VERSION 5.7 ;
  NOWIREEXTENSIONATPIN ON ;
  DIVIDERCHAR "/" ;
  BUSBITCHARS "[]" ;
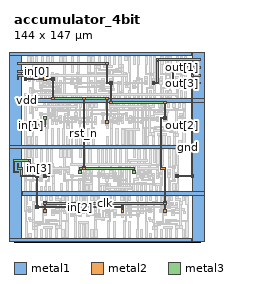
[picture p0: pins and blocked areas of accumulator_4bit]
MACRO accumulator_4bit
  CLASS BLOCK ;
  FOREIGN accumulator_4bit ;
  ORIGIN 6.000 0.000 ;
  SIZE 144.000 BY 147.000 ;
  PIN gnd
    USE GROUND ;
    PORT
      LAYER metal1 ;
        RECT 132.300 110.700 141.300 146.700 ;
        RECT 0.600 108.300 141.300 110.700 ;
        RECT 132.300 38.700 141.300 108.300 ;
        RECT 0.600 36.300 141.300 38.700 ;
        RECT 132.300 0.300 141.300 36.300 ;
    END
  END gnd
  PIN vdd
    USE POWER ;
    PORT
      LAYER metal1 ;
        RECT -9.300 144.300 131.400 146.700 ;
        RECT -9.300 74.700 -0.300 144.300 ;
        RECT -9.300 72.300 131.400 74.700 ;
        RECT -9.300 2.700 -0.300 72.300 ;
        RECT -9.300 0.300 131.400 2.700 ;
    END
  END vdd
  PIN clk
    PORT
      LAYER metal2 ;
        RECT 64.950 136.950 67.050 139.050 ;
        RECT 65.400 123.450 66.450 136.950 ;
        RECT 67.950 123.450 70.050 124.050 ;
        RECT 65.400 122.400 70.050 123.450 ;
        RECT 67.950 121.950 70.050 122.400 ;
        RECT 68.400 109.050 69.450 121.950 ;
        RECT 67.950 106.950 70.050 109.050 ;
        RECT 109.950 106.950 112.050 109.050 ;
        RECT 110.400 97.050 111.450 106.950 ;
        RECT 109.950 96.450 112.050 97.050 ;
        RECT 107.400 95.400 112.050 96.450 ;
        RECT 107.400 57.450 108.450 95.400 ;
        RECT 109.950 94.950 112.050 95.400 ;
        RECT 107.400 56.400 111.450 57.450 ;
        RECT 110.400 31.050 111.450 56.400 ;
        RECT 16.950 28.950 19.050 31.050 ;
        RECT 109.950 28.950 112.050 31.050 ;
        RECT 17.400 25.050 18.450 28.950 ;
        RECT 110.400 25.050 111.450 28.950 ;
        RECT 16.950 22.950 19.050 25.050 ;
        RECT 109.950 22.950 112.050 25.050 ;
      LAYER metal3 ;
        RECT 64.950 138.600 67.050 139.050 ;
        RECT -3.600 137.400 67.050 138.600 ;
        RECT 64.950 136.950 67.050 137.400 ;
        RECT 67.950 108.600 70.050 109.050 ;
        RECT 109.950 108.600 112.050 109.050 ;
        RECT 67.950 107.400 112.050 108.600 ;
        RECT 67.950 106.950 70.050 107.400 ;
        RECT 109.950 106.950 112.050 107.400 ;
        RECT 16.950 30.600 19.050 31.050 ;
        RECT 109.950 30.600 112.050 31.050 ;
        RECT 16.950 29.400 112.050 30.600 ;
        RECT 16.950 28.950 19.050 29.400 ;
        RECT 109.950 28.950 112.050 29.400 ;
    END
  END clk
  PIN rst_n
    PORT
      LAYER metal2 ;
        RECT 1.950 130.950 4.050 133.050 ;
        RECT 2.400 127.050 3.450 130.950 ;
        RECT 1.950 124.950 4.050 127.050 ;
        RECT 22.950 124.950 25.050 127.050 ;
        RECT 23.400 112.050 24.450 124.950 ;
        RECT 22.950 109.950 25.050 112.050 ;
        RECT 46.950 109.950 49.050 112.050 ;
        RECT 64.950 109.950 67.050 112.050 ;
        RECT 47.400 58.050 48.450 109.950 ;
        RECT 65.400 94.050 66.450 109.950 ;
        RECT 64.950 91.950 67.050 94.050 ;
        RECT 46.950 55.950 49.050 58.050 ;
        RECT 43.950 52.950 46.050 55.050 ;
        RECT 85.950 52.950 88.050 55.050 ;
      LAYER metal3 ;
        RECT 1.950 132.600 4.050 133.050 ;
        RECT -3.600 131.400 4.050 132.600 ;
        RECT 1.950 130.950 4.050 131.400 ;
        RECT 1.950 126.600 4.050 127.050 ;
        RECT 22.950 126.600 25.050 127.050 ;
        RECT 1.950 125.400 25.050 126.600 ;
        RECT 1.950 124.950 4.050 125.400 ;
        RECT 22.950 124.950 25.050 125.400 ;
        RECT 22.950 111.600 25.050 112.050 ;
        RECT 46.950 111.600 49.050 112.050 ;
        RECT 64.950 111.600 67.050 112.050 ;
        RECT 22.950 110.400 67.050 111.600 ;
        RECT 22.950 109.950 25.050 110.400 ;
        RECT 46.950 109.950 49.050 110.400 ;
        RECT 64.950 109.950 67.050 110.400 ;
        RECT 46.950 57.600 49.050 58.050 ;
        RECT 44.400 56.400 87.600 57.600 ;
        RECT 44.400 55.050 45.600 56.400 ;
        RECT 46.950 55.950 49.050 56.400 ;
        RECT 86.400 55.050 87.600 56.400 ;
        RECT 43.950 52.950 46.050 55.050 ;
        RECT 85.950 52.950 88.050 55.050 ;
    END
  END rst_n
  PIN in[3]
    PORT
      LAYER metal2 ;
        RECT 4.950 61.950 7.050 64.050 ;
        RECT 5.400 58.050 6.450 61.950 ;
        RECT 4.950 55.950 7.050 58.050 ;
        RECT 19.950 55.950 22.050 58.050 ;
        RECT 16.950 51.450 19.050 52.050 ;
        RECT 20.400 51.450 21.450 55.950 ;
        RECT 16.950 50.400 21.450 51.450 ;
        RECT 16.950 49.950 19.050 50.400 ;
      LAYER metal3 ;
        RECT 4.950 63.600 7.050 64.050 ;
        RECT -6.600 62.400 7.050 63.600 ;
        RECT -6.600 54.600 -5.400 62.400 ;
        RECT 4.950 61.950 7.050 62.400 ;
        RECT 4.950 57.600 7.050 58.050 ;
        RECT 19.950 57.600 22.050 58.050 ;
        RECT 4.950 56.400 22.050 57.600 ;
        RECT 4.950 55.950 7.050 56.400 ;
        RECT 19.950 55.950 22.050 56.400 ;
        RECT -6.600 53.400 -2.400 54.600 ;
    END
  END in[3]
  PIN in[2]
    PORT
      LAYER metal2 ;
        RECT 10.950 49.950 13.050 52.050 ;
        RECT 11.400 28.050 12.450 49.950 ;
        RECT 10.950 25.950 13.050 28.050 ;
        RECT 52.950 25.950 55.050 28.050 ;
        RECT 76.950 25.950 79.050 28.050 ;
        RECT 77.400 25.050 78.450 25.950 ;
        RECT 76.950 22.950 79.050 25.050 ;
      LAYER metal3 ;
        RECT -3.600 57.600 -2.400 60.600 ;
        RECT -3.600 56.400 0.600 57.600 ;
        RECT -0.600 51.600 0.600 56.400 ;
        RECT 10.950 51.600 13.050 52.050 ;
        RECT -0.600 50.400 13.050 51.600 ;
        RECT 10.950 49.950 13.050 50.400 ;
        RECT 10.950 27.600 13.050 28.050 ;
        RECT 52.950 27.600 55.050 28.050 ;
        RECT 76.950 27.600 79.050 28.050 ;
        RECT 10.950 26.400 79.050 27.600 ;
        RECT 10.950 25.950 13.050 26.400 ;
        RECT 52.950 25.950 55.050 26.400 ;
        RECT 76.950 25.950 79.050 26.400 ;
    END
  END in[2]
  PIN in[1]
    PORT
      LAYER metal2 ;
        RECT 16.950 94.950 19.050 97.050 ;
        RECT 4.950 88.950 7.050 91.050 ;
      LAYER metal3 ;
        RECT 16.950 94.950 19.050 97.050 ;
        RECT 4.950 90.600 7.050 91.050 ;
        RECT 17.400 90.600 18.600 94.950 ;
        RECT -3.600 89.400 18.600 90.600 ;
        RECT 4.950 88.950 7.050 89.400 ;
    END
  END in[1]
  PIN in[0]
    PORT
      LAYER metal2 ;
        RECT 4.950 130.950 7.050 133.050 ;
        RECT 16.950 130.950 19.050 133.050 ;
        RECT 5.400 130.050 6.450 130.950 ;
        RECT 4.950 127.950 7.050 130.050 ;
        RECT 17.400 127.050 18.450 130.950 ;
        RECT 16.950 124.950 19.050 127.050 ;
      LAYER metal3 ;
        RECT 4.950 132.600 7.050 133.050 ;
        RECT 16.950 132.600 19.050 133.050 ;
        RECT 4.950 131.400 19.050 132.600 ;
        RECT 4.950 130.950 7.050 131.400 ;
        RECT 16.950 130.950 19.050 131.400 ;
        RECT 4.950 129.600 7.050 130.050 ;
        RECT -3.600 128.400 7.050 129.600 ;
        RECT -3.600 125.400 -2.400 128.400 ;
        RECT 4.950 127.950 7.050 128.400 ;
    END
  END in[0]
  PIN out[3]
    PORT
      LAYER metal2 ;
        RECT 124.950 121.950 127.050 124.050 ;
      LAYER metal3 ;
        RECT 124.950 123.600 127.050 124.050 ;
        RECT 124.950 122.400 138.600 123.600 ;
        RECT 124.950 121.950 127.050 122.400 ;
    END
  END out[3]
  PIN out[2]
    PORT
      LAYER metal2 ;
        RECT 130.950 127.950 133.050 130.050 ;
        RECT 131.400 52.050 132.450 127.950 ;
        RECT 118.950 49.950 121.050 52.050 ;
        RECT 130.950 49.950 133.050 52.050 ;
      LAYER metal3 ;
        RECT 130.950 129.600 133.050 130.050 ;
        RECT 130.950 128.400 138.600 129.600 ;
        RECT 130.950 127.950 133.050 128.400 ;
        RECT 118.950 51.600 121.050 52.050 ;
        RECT 130.950 51.600 133.050 52.050 ;
        RECT 118.950 50.400 133.050 51.600 ;
        RECT 118.950 49.950 121.050 50.400 ;
        RECT 130.950 49.950 133.050 50.400 ;
    END
  END out[2]
  PIN out[1]
    PORT
      LAYER metal2 ;
        RECT 115.950 133.950 118.050 136.050 ;
        RECT 112.950 123.450 115.050 124.050 ;
        RECT 116.400 123.450 117.450 133.950 ;
        RECT 112.950 122.400 117.450 123.450 ;
        RECT 112.950 121.950 115.050 122.400 ;
      LAYER metal3 ;
        RECT 115.950 135.600 118.050 136.050 ;
        RECT 115.950 134.400 138.600 135.600 ;
        RECT 115.950 133.950 118.050 134.400 ;
    END
  END out[1]
  PIN out[0]
    PORT
      LAYER metal2 ;
        RECT 103.950 139.950 106.050 142.050 ;
        RECT 100.950 123.450 103.050 124.050 ;
        RECT 104.400 123.450 105.450 139.950 ;
        RECT 100.950 122.400 105.450 123.450 ;
        RECT 100.950 121.950 103.050 122.400 ;
      LAYER metal3 ;
        RECT 103.950 141.600 106.050 142.050 ;
        RECT 103.950 140.400 138.600 141.600 ;
        RECT 103.950 139.950 106.050 140.400 ;
    END
  END out[0]
  OBS
      LAYER metal1 ;
        RECT 4.650 137.400 6.450 143.250 ;
        RECT 7.650 137.400 9.450 143.250 ;
        RECT 10.650 137.400 12.450 143.250 ;
        RECT 8.250 129.150 9.450 137.400 ;
        RECT 15.300 131.400 17.100 143.250 ;
        RECT 19.500 131.400 21.300 143.250 ;
        RECT 22.800 137.400 24.600 143.250 ;
        RECT 29.550 137.400 31.350 143.250 ;
        RECT 32.550 137.400 34.350 143.250 ;
        RECT 4.950 125.850 7.050 127.950 ;
        RECT 7.950 127.050 10.050 129.150 ;
        RECT 5.100 124.050 6.900 125.850 ;
        RECT 8.250 119.700 9.450 127.050 ;
        RECT 10.950 125.850 13.050 127.950 ;
        RECT 14.100 126.150 15.900 127.950 ;
        RECT 19.950 126.150 21.150 131.400 ;
        RECT 22.950 129.150 24.750 130.950 ;
        RECT 22.950 127.050 25.050 129.150 ;
        RECT 11.100 124.050 12.900 125.850 ;
        RECT 13.950 124.050 16.050 126.150 ;
        RECT 16.950 122.850 19.050 124.950 ;
        RECT 19.950 124.050 22.050 126.150 ;
        RECT 32.400 124.950 33.600 137.400 ;
        RECT 38.550 131.400 40.350 143.250 ;
        RECT 42.750 131.400 44.550 143.250 ;
        RECT 42.000 130.350 44.550 131.400 ;
        RECT 51.150 131.400 52.950 143.250 ;
        RECT 54.150 137.400 55.950 143.250 ;
        RECT 59.250 137.400 61.050 143.250 ;
        RECT 64.050 137.400 65.850 143.250 ;
        RECT 59.550 136.500 60.750 137.400 ;
        RECT 67.050 136.500 68.850 143.250 ;
        RECT 70.950 137.400 72.750 143.250 ;
        RECT 75.150 137.400 76.950 143.250 ;
        RECT 79.650 140.400 81.450 143.250 ;
        RECT 55.950 134.400 60.750 136.500 ;
        RECT 63.150 134.700 70.050 136.500 ;
        RECT 75.150 135.300 79.050 137.400 ;
        RECT 59.550 133.500 60.750 134.400 ;
        RECT 72.450 133.800 74.250 134.400 ;
        RECT 59.550 132.300 67.050 133.500 ;
        RECT 65.250 131.700 67.050 132.300 ;
        RECT 67.950 132.900 74.250 133.800 ;
        RECT 51.150 130.800 62.250 131.400 ;
        RECT 67.950 130.800 68.850 132.900 ;
        RECT 72.450 132.600 74.250 132.900 ;
        RECT 75.150 132.600 77.850 134.400 ;
        RECT 75.150 131.700 76.050 132.600 ;
        RECT 38.100 126.150 39.900 127.950 ;
        RECT 17.100 121.050 18.900 122.850 ;
        RECT 20.850 120.750 22.050 124.050 ;
        RECT 29.100 123.150 30.900 124.950 ;
        RECT 28.950 121.050 31.050 123.150 ;
        RECT 31.950 122.850 34.050 124.950 ;
        RECT 37.950 124.050 40.050 126.150 ;
        RECT 42.000 123.150 43.050 130.350 ;
        RECT 51.150 130.200 68.850 130.800 ;
        RECT 44.100 126.150 45.900 127.950 ;
        RECT 43.950 124.050 46.050 126.150 ;
        RECT 21.000 119.700 24.750 120.750 ;
        RECT 5.850 118.800 9.450 119.700 ;
        RECT 5.850 111.750 7.650 118.800 ;
        RECT 10.350 111.750 12.150 117.600 ;
        RECT 14.550 116.700 22.350 118.050 ;
        RECT 14.550 111.750 16.350 116.700 ;
        RECT 17.550 111.750 19.350 115.800 ;
        RECT 20.550 111.750 22.350 116.700 ;
        RECT 23.550 117.600 24.750 119.700 ;
        RECT 23.550 111.750 25.350 117.600 ;
        RECT 32.400 114.600 33.600 122.850 ;
        RECT 40.950 121.050 43.050 123.150 ;
        RECT 42.000 114.600 43.050 121.050 ;
        RECT 51.150 117.600 52.050 130.200 ;
        RECT 60.450 129.900 68.850 130.200 ;
        RECT 70.050 130.800 76.050 131.700 ;
        RECT 76.950 130.800 79.050 131.700 ;
        RECT 82.650 131.400 84.450 143.250 ;
        RECT 86.550 137.400 88.350 143.250 ;
        RECT 89.550 137.400 91.350 143.250 ;
        RECT 95.550 137.400 97.350 143.250 ;
        RECT 60.450 129.600 62.250 129.900 ;
        RECT 70.050 126.150 70.950 130.800 ;
        RECT 76.950 129.600 81.150 130.800 ;
        RECT 80.250 127.800 82.050 129.600 ;
        RECT 61.950 125.100 64.050 126.150 ;
        RECT 53.100 123.150 54.900 124.950 ;
        RECT 56.100 124.050 64.050 125.100 ;
        RECT 67.950 124.050 70.950 126.150 ;
        RECT 56.100 123.300 57.900 124.050 ;
        RECT 54.000 122.400 54.900 123.150 ;
        RECT 59.100 122.400 60.900 123.000 ;
        RECT 54.000 121.200 60.900 122.400 ;
        RECT 59.850 120.000 60.900 121.200 ;
        RECT 70.050 120.000 70.950 124.050 ;
        RECT 79.950 123.750 82.050 124.050 ;
        RECT 78.150 121.950 82.050 123.750 ;
        RECT 83.250 121.950 84.450 131.400 ;
        RECT 89.400 124.950 90.600 137.400 ;
        RECT 95.550 130.500 96.750 137.400 ;
        RECT 98.850 131.400 100.650 143.250 ;
        RECT 101.850 131.400 103.650 143.250 ;
        RECT 107.550 137.400 109.350 143.250 ;
        RECT 95.550 129.600 101.250 130.500 ;
        RECT 99.000 128.700 101.250 129.600 ;
        RECT 95.100 126.150 96.900 127.950 ;
        RECT 86.100 123.150 87.900 124.950 ;
        RECT 59.850 119.100 70.950 120.000 ;
        RECT 79.950 119.850 84.450 121.950 ;
        RECT 85.950 121.050 88.050 123.150 ;
        RECT 88.950 122.850 91.050 124.950 ;
        RECT 94.950 124.050 97.050 126.150 ;
        RECT 59.850 118.200 60.900 119.100 ;
        RECT 70.050 118.800 70.950 119.100 ;
        RECT 29.550 111.750 31.350 114.600 ;
        RECT 32.550 111.750 34.350 114.600 ;
        RECT 38.550 111.750 40.350 114.600 ;
        RECT 41.550 111.750 43.350 114.600 ;
        RECT 44.550 111.750 46.350 114.600 ;
        RECT 51.150 111.750 52.950 117.600 ;
        RECT 55.950 115.500 58.050 117.600 ;
        RECT 59.550 116.400 61.350 118.200 ;
        RECT 62.850 117.450 64.650 118.200 ;
        RECT 62.850 116.400 67.800 117.450 ;
        RECT 70.050 117.000 71.850 118.800 ;
        RECT 83.250 117.600 84.450 119.850 ;
        RECT 76.950 116.700 79.050 117.600 ;
        RECT 57.000 114.600 58.050 115.500 ;
        RECT 66.750 114.600 67.800 116.400 ;
        RECT 75.300 115.500 79.050 116.700 ;
        RECT 75.300 114.600 76.350 115.500 ;
        RECT 54.150 111.750 55.950 114.600 ;
        RECT 57.000 113.700 60.750 114.600 ;
        RECT 58.950 111.750 60.750 113.700 ;
        RECT 63.450 111.750 65.250 114.600 ;
        RECT 66.750 111.750 68.550 114.600 ;
        RECT 70.650 111.750 72.450 114.600 ;
        RECT 74.850 111.750 76.650 114.600 ;
        RECT 79.350 111.750 81.150 114.600 ;
        RECT 82.650 111.750 84.450 117.600 ;
        RECT 89.400 114.600 90.600 122.850 ;
        RECT 99.000 120.300 100.050 128.700 ;
        RECT 102.150 126.150 103.350 131.400 ;
        RECT 107.550 130.500 108.750 137.400 ;
        RECT 110.850 131.400 112.650 143.250 ;
        RECT 113.850 131.400 115.650 143.250 ;
        RECT 119.550 137.400 121.350 143.250 ;
        RECT 107.550 129.600 113.250 130.500 ;
        RECT 111.000 128.700 113.250 129.600 ;
        RECT 107.100 126.150 108.900 127.950 ;
        RECT 100.950 124.050 103.350 126.150 ;
        RECT 106.950 124.050 109.050 126.150 ;
        RECT 99.000 119.400 101.250 120.300 ;
        RECT 96.150 118.500 101.250 119.400 ;
        RECT 96.150 114.600 97.350 118.500 ;
        RECT 102.150 117.600 103.350 124.050 ;
        RECT 111.000 120.300 112.050 128.700 ;
        RECT 114.150 126.150 115.350 131.400 ;
        RECT 119.550 130.500 120.750 137.400 ;
        RECT 122.850 131.400 124.650 143.250 ;
        RECT 125.850 131.400 127.650 143.250 ;
        RECT 119.550 129.600 125.250 130.500 ;
        RECT 123.000 128.700 125.250 129.600 ;
        RECT 119.100 126.150 120.900 127.950 ;
        RECT 112.950 124.050 115.350 126.150 ;
        RECT 118.950 124.050 121.050 126.150 ;
        RECT 111.000 119.400 113.250 120.300 ;
        RECT 108.150 118.500 113.250 119.400 ;
        RECT 86.550 111.750 88.350 114.600 ;
        RECT 89.550 111.750 91.350 114.600 ;
        RECT 95.550 111.750 97.350 114.600 ;
        RECT 98.850 111.750 100.650 117.600 ;
        RECT 101.850 111.750 103.650 117.600 ;
        RECT 108.150 114.600 109.350 118.500 ;
        RECT 114.150 117.600 115.350 124.050 ;
        RECT 123.000 120.300 124.050 128.700 ;
        RECT 126.150 126.150 127.350 131.400 ;
        RECT 124.950 124.050 127.350 126.150 ;
        RECT 123.000 119.400 125.250 120.300 ;
        RECT 120.150 118.500 125.250 119.400 ;
        RECT 107.550 111.750 109.350 114.600 ;
        RECT 110.850 111.750 112.650 117.600 ;
        RECT 113.850 111.750 115.650 117.600 ;
        RECT 120.150 114.600 121.350 118.500 ;
        RECT 126.150 117.600 127.350 124.050 ;
        RECT 119.550 111.750 121.350 114.600 ;
        RECT 122.850 111.750 124.650 117.600 ;
        RECT 125.850 111.750 127.650 117.600 ;
        RECT 5.850 100.200 7.650 107.250 ;
        RECT 10.350 101.400 12.150 107.250 ;
        RECT 16.650 104.400 18.450 107.250 ;
        RECT 19.650 104.400 21.450 107.250 ;
        RECT 22.650 104.400 24.450 107.250 ;
        RECT 5.850 99.300 9.450 100.200 ;
        RECT 5.100 93.150 6.900 94.950 ;
        RECT 4.950 91.050 7.050 93.150 ;
        RECT 8.250 91.950 9.450 99.300 ;
        RECT 19.950 97.950 21.000 104.400 ;
        RECT 26.550 102.300 28.350 107.250 ;
        RECT 29.550 103.200 31.350 107.250 ;
        RECT 32.550 102.300 34.350 107.250 ;
        RECT 26.550 100.950 34.350 102.300 ;
        RECT 35.550 101.400 37.350 107.250 ;
        RECT 41.550 104.400 43.350 107.250 ;
        RECT 44.550 104.400 46.350 107.250 ;
        RECT 50.550 104.400 52.350 107.250 ;
        RECT 53.550 104.400 55.350 107.250 ;
        RECT 56.550 104.400 58.350 107.250 ;
        RECT 35.550 99.300 36.750 101.400 ;
        RECT 33.000 98.250 36.750 99.300 ;
        RECT 19.950 95.850 22.050 97.950 ;
        RECT 29.100 96.150 30.900 97.950 ;
        RECT 11.100 93.150 12.900 94.950 ;
        RECT 7.950 89.850 10.050 91.950 ;
        RECT 10.950 91.050 13.050 93.150 ;
        RECT 16.950 92.850 19.050 94.950 ;
        RECT 17.100 91.050 18.900 92.850 ;
        RECT 8.250 81.600 9.450 89.850 ;
        RECT 19.950 88.650 21.000 95.850 ;
        RECT 22.950 92.850 25.050 94.950 ;
        RECT 25.950 92.850 28.050 94.950 ;
        RECT 28.950 94.050 31.050 96.150 ;
        RECT 32.850 94.950 34.050 98.250 ;
        RECT 40.950 95.850 43.050 97.950 ;
        RECT 44.400 96.150 45.600 104.400 ;
        RECT 54.000 97.950 55.050 104.400 ;
        RECT 64.650 101.400 66.450 107.250 ;
        RECT 65.250 99.300 66.450 101.400 ;
        RECT 67.650 102.300 69.450 107.250 ;
        RECT 70.650 103.200 72.450 107.250 ;
        RECT 73.650 102.300 75.450 107.250 ;
        RECT 67.650 100.950 75.450 102.300 ;
        RECT 78.000 101.400 79.800 107.250 ;
        RECT 82.200 103.050 84.000 107.250 ;
        RECT 85.500 104.400 87.300 107.250 ;
        RECT 82.200 101.400 87.900 103.050 ;
        RECT 65.250 98.250 69.000 99.300 ;
        RECT 31.950 92.850 34.050 94.950 ;
        RECT 41.100 94.050 42.900 95.850 ;
        RECT 43.950 94.050 46.050 96.150 ;
        RECT 52.950 95.850 55.050 97.950 ;
        RECT 23.100 91.050 24.900 92.850 ;
        RECT 26.100 91.050 27.900 92.850 ;
        RECT 18.450 87.600 21.000 88.650 ;
        RECT 31.950 87.600 33.150 92.850 ;
        RECT 34.950 89.850 37.050 91.950 ;
        RECT 34.950 88.050 36.750 89.850 ;
        RECT 4.650 75.750 6.450 81.600 ;
        RECT 7.650 75.750 9.450 81.600 ;
        RECT 10.650 75.750 12.450 81.600 ;
        RECT 18.450 75.750 20.250 87.600 ;
        RECT 22.650 75.750 24.450 87.600 ;
        RECT 27.300 75.750 29.100 87.600 ;
        RECT 31.500 75.750 33.300 87.600 ;
        RECT 44.400 81.600 45.600 94.050 ;
        RECT 49.950 92.850 52.050 94.950 ;
        RECT 50.100 91.050 51.900 92.850 ;
        RECT 54.000 88.650 55.050 95.850 ;
        RECT 67.950 94.950 69.150 98.250 ;
        RECT 71.100 96.150 72.900 97.950 ;
        RECT 77.100 96.150 78.900 97.950 ;
        RECT 55.950 92.850 58.050 94.950 ;
        RECT 67.950 92.850 70.050 94.950 ;
        RECT 70.950 94.050 73.050 96.150 ;
        RECT 73.950 92.850 76.050 94.950 ;
        RECT 76.950 94.050 79.050 96.150 ;
        RECT 79.950 95.850 82.050 97.950 ;
        RECT 83.100 96.150 84.900 97.950 ;
        RECT 80.100 94.050 81.900 95.850 ;
        RECT 82.950 94.050 85.050 96.150 ;
        RECT 86.700 94.950 87.900 101.400 ;
        RECT 93.150 101.400 94.950 107.250 ;
        RECT 96.150 104.400 97.950 107.250 ;
        RECT 100.950 105.300 102.750 107.250 ;
        RECT 99.000 104.400 102.750 105.300 ;
        RECT 105.450 104.400 107.250 107.250 ;
        RECT 108.750 104.400 110.550 107.250 ;
        RECT 112.650 104.400 114.450 107.250 ;
        RECT 116.850 104.400 118.650 107.250 ;
        RECT 121.350 104.400 123.150 107.250 ;
        RECT 99.000 103.500 100.050 104.400 ;
        RECT 97.950 101.400 100.050 103.500 ;
        RECT 108.750 102.600 109.800 104.400 ;
        RECT 85.950 92.850 88.050 94.950 ;
        RECT 56.100 91.050 57.900 92.850 ;
        RECT 64.950 89.850 67.050 91.950 ;
        RECT 54.000 87.600 56.550 88.650 ;
        RECT 65.250 88.050 67.050 89.850 ;
        RECT 68.850 87.600 70.050 92.850 ;
        RECT 74.100 91.050 75.900 92.850 ;
        RECT 86.700 87.600 87.900 92.850 ;
        RECT 93.150 88.800 94.050 101.400 ;
        RECT 101.550 100.800 103.350 102.600 ;
        RECT 104.850 101.550 109.800 102.600 ;
        RECT 117.300 103.500 118.350 104.400 ;
        RECT 117.300 102.300 121.050 103.500 ;
        RECT 104.850 100.800 106.650 101.550 ;
        RECT 101.850 99.900 102.900 100.800 ;
        RECT 112.050 100.200 113.850 102.000 ;
        RECT 118.950 101.400 121.050 102.300 ;
        RECT 124.650 101.400 126.450 107.250 ;
        RECT 112.050 99.900 112.950 100.200 ;
        RECT 101.850 99.000 112.950 99.900 ;
        RECT 125.250 99.150 126.450 101.400 ;
        RECT 101.850 97.800 102.900 99.000 ;
        RECT 96.000 96.600 102.900 97.800 ;
        RECT 96.000 95.850 96.900 96.600 ;
        RECT 101.100 96.000 102.900 96.600 ;
        RECT 95.100 94.050 96.900 95.850 ;
        RECT 98.100 94.950 99.900 95.700 ;
        RECT 112.050 94.950 112.950 99.000 ;
        RECT 121.950 97.050 126.450 99.150 ;
        RECT 120.150 95.250 124.050 97.050 ;
        RECT 121.950 94.950 124.050 95.250 ;
        RECT 98.100 93.900 106.050 94.950 ;
        RECT 103.950 92.850 106.050 93.900 ;
        RECT 109.950 92.850 112.950 94.950 ;
        RECT 102.450 89.100 104.250 89.400 ;
        RECT 102.450 88.800 110.850 89.100 ;
        RECT 93.150 88.200 110.850 88.800 ;
        RECT 93.150 87.600 104.250 88.200 ;
        RECT 34.800 75.750 36.600 81.600 ;
        RECT 41.550 75.750 43.350 81.600 ;
        RECT 44.550 75.750 46.350 81.600 ;
        RECT 50.550 75.750 52.350 87.600 ;
        RECT 54.750 75.750 56.550 87.600 ;
        RECT 65.400 75.750 67.200 81.600 ;
        RECT 68.700 75.750 70.500 87.600 ;
        RECT 72.900 75.750 74.700 87.600 ;
        RECT 77.550 86.700 85.350 87.600 ;
        RECT 77.550 75.750 79.350 86.700 ;
        RECT 80.550 75.750 82.350 85.800 ;
        RECT 83.550 75.750 85.350 86.700 ;
        RECT 86.550 75.750 88.350 87.600 ;
        RECT 93.150 75.750 94.950 87.600 ;
        RECT 107.250 86.700 109.050 87.300 ;
        RECT 101.550 85.500 109.050 86.700 ;
        RECT 109.950 86.100 110.850 88.200 ;
        RECT 112.050 88.200 112.950 92.850 ;
        RECT 122.250 89.400 124.050 91.200 ;
        RECT 118.950 88.200 123.150 89.400 ;
        RECT 112.050 87.300 118.050 88.200 ;
        RECT 118.950 87.300 121.050 88.200 ;
        RECT 125.250 87.600 126.450 97.050 ;
        RECT 117.150 86.400 118.050 87.300 ;
        RECT 114.450 86.100 116.250 86.400 ;
        RECT 101.550 84.600 102.750 85.500 ;
        RECT 109.950 85.200 116.250 86.100 ;
        RECT 114.450 84.600 116.250 85.200 ;
        RECT 117.150 84.600 119.850 86.400 ;
        RECT 97.950 82.500 102.750 84.600 ;
        RECT 105.150 82.500 112.050 84.300 ;
        RECT 101.550 81.600 102.750 82.500 ;
        RECT 96.150 75.750 97.950 81.600 ;
        RECT 101.250 75.750 103.050 81.600 ;
        RECT 106.050 75.750 107.850 81.600 ;
        RECT 109.050 75.750 110.850 82.500 ;
        RECT 117.150 81.600 121.050 83.700 ;
        RECT 112.950 75.750 114.750 81.600 ;
        RECT 117.150 75.750 118.950 81.600 ;
        RECT 121.650 75.750 123.450 78.600 ;
        RECT 124.650 75.750 126.450 87.600 ;
        RECT 4.650 65.400 6.450 71.250 ;
        RECT 7.650 65.400 9.450 71.250 ;
        RECT 10.650 65.400 12.450 71.250 ;
        RECT 8.250 57.150 9.450 65.400 ;
        RECT 14.550 59.400 16.350 71.250 ;
        RECT 19.050 59.550 20.850 71.250 ;
        RECT 22.050 60.900 23.850 71.250 ;
        RECT 29.550 65.400 31.350 71.250 ;
        RECT 32.550 65.400 34.350 71.250 ;
        RECT 35.550 65.400 37.350 71.250 ;
        RECT 44.400 65.400 46.200 71.250 ;
        RECT 22.050 59.550 24.450 60.900 ;
        RECT 14.550 58.200 15.750 59.400 ;
        RECT 19.950 58.200 21.750 58.650 ;
        RECT 4.950 53.850 7.050 55.950 ;
        RECT 7.950 55.050 10.050 57.150 ;
        RECT 14.550 57.000 21.750 58.200 ;
        RECT 19.950 56.850 21.750 57.000 ;
        RECT 5.100 52.050 6.900 53.850 ;
        RECT 8.250 47.700 9.450 55.050 ;
        RECT 10.950 53.850 13.050 55.950 ;
        RECT 17.100 54.150 18.900 55.950 ;
        RECT 11.100 52.050 12.900 53.850 ;
        RECT 14.100 51.150 15.900 52.950 ;
        RECT 16.950 52.050 19.050 54.150 ;
        RECT 13.950 49.050 16.050 51.150 ;
        RECT 20.700 48.600 21.600 56.850 ;
        RECT 23.100 52.950 24.450 59.550 ;
        RECT 32.550 57.150 33.750 65.400 ;
        RECT 47.700 59.400 49.500 71.250 ;
        RECT 51.900 59.400 53.700 71.250 ;
        RECT 58.650 59.400 60.450 71.250 ;
        RECT 61.650 60.300 63.450 71.250 ;
        RECT 64.650 61.200 66.450 71.250 ;
        RECT 67.650 60.300 69.450 71.250 ;
        RECT 61.650 59.400 69.450 60.300 ;
        RECT 71.550 59.400 73.350 71.250 ;
        RECT 75.750 59.400 77.550 71.250 ;
        RECT 86.400 65.400 88.200 71.250 ;
        RECT 89.700 59.400 91.500 71.250 ;
        RECT 93.900 59.400 95.700 71.250 ;
        RECT 98.550 60.300 100.350 71.250 ;
        RECT 101.550 61.200 103.350 71.250 ;
        RECT 104.550 60.300 106.350 71.250 ;
        RECT 98.550 59.400 106.350 60.300 ;
        RECT 107.550 59.400 109.350 71.250 ;
        RECT 113.550 65.400 115.350 71.250 ;
        RECT 44.250 57.150 46.050 58.950 ;
        RECT 28.950 53.850 31.050 55.950 ;
        RECT 31.950 55.050 34.050 57.150 ;
        RECT 22.950 50.850 25.050 52.950 ;
        RECT 29.100 52.050 30.900 53.850 ;
        RECT 19.950 47.700 21.750 48.600 ;
        RECT 5.850 46.800 9.450 47.700 ;
        RECT 18.450 46.800 21.750 47.700 ;
        RECT 5.850 39.750 7.650 46.800 ;
        RECT 10.350 39.750 12.150 45.600 ;
        RECT 18.450 42.600 19.350 46.800 ;
        RECT 24.000 45.600 25.050 50.850 ;
        RECT 32.550 47.700 33.750 55.050 ;
        RECT 34.950 53.850 37.050 55.950 ;
        RECT 43.950 55.050 46.050 57.150 ;
        RECT 47.850 54.150 49.050 59.400 ;
        RECT 53.100 54.150 54.900 55.950 ;
        RECT 59.100 54.150 60.300 59.400 ;
        RECT 75.000 58.350 77.550 59.400 ;
        RECT 71.100 54.150 72.900 55.950 ;
        RECT 35.100 52.050 36.900 53.850 ;
        RECT 46.950 52.050 49.050 54.150 ;
        RECT 46.950 48.750 48.150 52.050 ;
        RECT 49.950 50.850 52.050 52.950 ;
        RECT 52.950 52.050 55.050 54.150 ;
        RECT 58.950 52.050 61.050 54.150 ;
        RECT 50.100 49.050 51.900 50.850 ;
        RECT 44.250 47.700 48.000 48.750 ;
        RECT 32.550 46.800 36.150 47.700 ;
        RECT 14.550 39.750 16.350 42.600 ;
        RECT 17.550 39.750 19.350 42.600 ;
        RECT 20.550 39.750 22.350 42.600 ;
        RECT 23.550 39.750 25.350 45.600 ;
        RECT 29.850 39.750 31.650 45.600 ;
        RECT 34.350 39.750 36.150 46.800 ;
        RECT 44.250 45.600 45.450 47.700 ;
        RECT 43.650 39.750 45.450 45.600 ;
        RECT 46.650 44.700 54.450 46.050 ;
        RECT 46.650 39.750 48.450 44.700 ;
        RECT 49.650 39.750 51.450 43.800 ;
        RECT 52.650 39.750 54.450 44.700 ;
        RECT 59.100 45.600 60.300 52.050 ;
        RECT 61.950 50.850 64.050 52.950 ;
        RECT 65.100 51.150 66.900 52.950 ;
        RECT 62.100 49.050 63.900 50.850 ;
        RECT 64.950 49.050 67.050 51.150 ;
        RECT 67.950 50.850 70.050 52.950 ;
        RECT 70.950 52.050 73.050 54.150 ;
        RECT 75.000 51.150 76.050 58.350 ;
        RECT 86.250 57.150 88.050 58.950 ;
        RECT 77.100 54.150 78.900 55.950 ;
        RECT 85.950 55.050 88.050 57.150 ;
        RECT 89.850 54.150 91.050 59.400 ;
        RECT 95.100 54.150 96.900 55.950 ;
        RECT 107.700 54.150 108.900 59.400 ;
        RECT 113.550 58.500 114.750 65.400 ;
        RECT 116.850 59.400 118.650 71.250 ;
        RECT 119.850 59.400 121.650 71.250 ;
        RECT 113.550 57.600 119.250 58.500 ;
        RECT 117.000 56.700 119.250 57.600 ;
        RECT 113.100 54.150 114.900 55.950 ;
        RECT 76.950 52.050 79.050 54.150 ;
        RECT 88.950 52.050 91.050 54.150 ;
        RECT 68.100 49.050 69.900 50.850 ;
        RECT 73.950 49.050 76.050 51.150 ;
        RECT 59.100 43.950 64.800 45.600 ;
        RECT 59.700 39.750 61.500 42.600 ;
        RECT 63.000 39.750 64.800 43.950 ;
        RECT 67.200 39.750 69.000 45.600 ;
        RECT 75.000 42.600 76.050 49.050 ;
        RECT 88.950 48.750 90.150 52.050 ;
        RECT 91.950 50.850 94.050 52.950 ;
        RECT 94.950 52.050 97.050 54.150 ;
        RECT 97.950 50.850 100.050 52.950 ;
        RECT 101.100 51.150 102.900 52.950 ;
        RECT 92.100 49.050 93.900 50.850 ;
        RECT 98.100 49.050 99.900 50.850 ;
        RECT 100.950 49.050 103.050 51.150 ;
        RECT 103.950 50.850 106.050 52.950 ;
        RECT 106.950 52.050 109.050 54.150 ;
        RECT 112.950 52.050 115.050 54.150 ;
        RECT 104.100 49.050 105.900 50.850 ;
        RECT 86.250 47.700 90.000 48.750 ;
        RECT 86.250 45.600 87.450 47.700 ;
        RECT 71.550 39.750 73.350 42.600 ;
        RECT 74.550 39.750 76.350 42.600 ;
        RECT 77.550 39.750 79.350 42.600 ;
        RECT 85.650 39.750 87.450 45.600 ;
        RECT 88.650 44.700 96.450 46.050 ;
        RECT 107.700 45.600 108.900 52.050 ;
        RECT 117.000 48.300 118.050 56.700 ;
        RECT 120.150 54.150 121.350 59.400 ;
        RECT 118.950 52.050 121.350 54.150 ;
        RECT 117.000 47.400 119.250 48.300 ;
        RECT 88.650 39.750 90.450 44.700 ;
        RECT 91.650 39.750 93.450 43.800 ;
        RECT 94.650 39.750 96.450 44.700 ;
        RECT 99.000 39.750 100.800 45.600 ;
        RECT 103.200 43.950 108.900 45.600 ;
        RECT 114.150 46.500 119.250 47.400 ;
        RECT 103.200 39.750 105.000 43.950 ;
        RECT 114.150 42.600 115.350 46.500 ;
        RECT 120.150 45.600 121.350 52.050 ;
        RECT 106.500 39.750 108.300 42.600 ;
        RECT 113.550 39.750 115.350 42.600 ;
        RECT 116.850 39.750 118.650 45.600 ;
        RECT 119.850 39.750 121.650 45.600 ;
        RECT 2.550 29.400 4.350 35.250 ;
        RECT 5.850 32.400 7.650 35.250 ;
        RECT 10.350 32.400 12.150 35.250 ;
        RECT 14.550 32.400 16.350 35.250 ;
        RECT 18.450 32.400 20.250 35.250 ;
        RECT 21.750 32.400 23.550 35.250 ;
        RECT 26.250 33.300 28.050 35.250 ;
        RECT 26.250 32.400 30.000 33.300 ;
        RECT 31.050 32.400 32.850 35.250 ;
        RECT 10.650 31.500 11.700 32.400 ;
        RECT 7.950 30.300 11.700 31.500 ;
        RECT 19.200 30.600 20.250 32.400 ;
        RECT 28.950 31.500 30.000 32.400 ;
        RECT 7.950 29.400 10.050 30.300 ;
        RECT 2.550 27.150 3.750 29.400 ;
        RECT 15.150 28.200 16.950 30.000 ;
        RECT 19.200 29.550 24.150 30.600 ;
        RECT 22.350 28.800 24.150 29.550 ;
        RECT 25.650 28.800 27.450 30.600 ;
        RECT 28.950 29.400 31.050 31.500 ;
        RECT 34.050 29.400 35.850 35.250 ;
        RECT 41.700 32.400 43.500 35.250 ;
        RECT 45.000 31.050 46.800 35.250 ;
        RECT 16.050 27.900 16.950 28.200 ;
        RECT 26.100 27.900 27.150 28.800 ;
        RECT 2.550 25.050 7.050 27.150 ;
        RECT 16.050 27.000 27.150 27.900 ;
        RECT 2.550 15.600 3.750 25.050 ;
        RECT 4.950 23.250 8.850 25.050 ;
        RECT 4.950 22.950 7.050 23.250 ;
        RECT 16.050 22.950 16.950 27.000 ;
        RECT 26.100 25.800 27.150 27.000 ;
        RECT 26.100 24.600 33.000 25.800 ;
        RECT 26.100 24.000 27.900 24.600 ;
        RECT 32.100 23.850 33.000 24.600 ;
        RECT 29.100 22.950 30.900 23.700 ;
        RECT 16.050 20.850 19.050 22.950 ;
        RECT 22.950 21.900 30.900 22.950 ;
        RECT 32.100 22.050 33.900 23.850 ;
        RECT 22.950 20.850 25.050 21.900 ;
        RECT 4.950 17.400 6.750 19.200 ;
        RECT 5.850 16.200 10.050 17.400 ;
        RECT 16.050 16.200 16.950 20.850 ;
        RECT 24.750 17.100 26.550 17.400 ;
        RECT 2.550 3.750 4.350 15.600 ;
        RECT 7.950 15.300 10.050 16.200 ;
        RECT 10.950 15.300 16.950 16.200 ;
        RECT 18.150 16.800 26.550 17.100 ;
        RECT 34.950 16.800 35.850 29.400 ;
        RECT 41.100 29.400 46.800 31.050 ;
        RECT 49.200 29.400 51.000 35.250 ;
        RECT 53.550 32.400 55.350 35.250 ;
        RECT 56.550 32.400 58.350 35.250 ;
        RECT 64.650 32.400 66.450 35.250 ;
        RECT 67.650 32.400 69.450 35.250 ;
        RECT 70.650 32.400 72.450 35.250 ;
        RECT 76.650 32.400 78.450 35.250 ;
        RECT 79.650 32.400 81.450 35.250 ;
        RECT 82.650 32.400 84.450 35.250 ;
        RECT 88.650 32.400 90.450 35.250 ;
        RECT 91.650 32.400 93.450 35.250 ;
        RECT 41.100 22.950 42.300 29.400 ;
        RECT 44.100 24.150 45.900 25.950 ;
        RECT 40.950 20.850 43.050 22.950 ;
        RECT 43.950 22.050 46.050 24.150 ;
        RECT 46.950 23.850 49.050 25.950 ;
        RECT 50.100 24.150 51.900 25.950 ;
        RECT 47.100 22.050 48.900 23.850 ;
        RECT 49.950 22.050 52.050 24.150 ;
        RECT 52.950 23.850 55.050 25.950 ;
        RECT 56.400 24.150 57.600 32.400 ;
        RECT 67.950 25.950 69.000 32.400 ;
        RECT 79.950 25.950 81.000 32.400 ;
        RECT 53.100 22.050 54.900 23.850 ;
        RECT 55.950 22.050 58.050 24.150 ;
        RECT 67.950 23.850 70.050 25.950 ;
        RECT 79.950 23.850 82.050 25.950 ;
        RECT 89.400 24.150 90.600 32.400 ;
        RECT 95.550 29.400 97.350 35.250 ;
        RECT 98.850 32.400 100.650 35.250 ;
        RECT 103.350 32.400 105.150 35.250 ;
        RECT 107.550 32.400 109.350 35.250 ;
        RECT 111.450 32.400 113.250 35.250 ;
        RECT 114.750 32.400 116.550 35.250 ;
        RECT 119.250 33.300 121.050 35.250 ;
        RECT 119.250 32.400 123.000 33.300 ;
        RECT 124.050 32.400 125.850 35.250 ;
        RECT 103.650 31.500 104.700 32.400 ;
        RECT 100.950 30.300 104.700 31.500 ;
        RECT 112.200 30.600 113.250 32.400 ;
        RECT 121.950 31.500 123.000 32.400 ;
        RECT 100.950 29.400 103.050 30.300 ;
        RECT 95.550 27.150 96.750 29.400 ;
        RECT 108.150 28.200 109.950 30.000 ;
        RECT 112.200 29.550 117.150 30.600 ;
        RECT 115.350 28.800 117.150 29.550 ;
        RECT 118.650 28.800 120.450 30.600 ;
        RECT 121.950 29.400 124.050 31.500 ;
        RECT 127.050 29.400 128.850 35.250 ;
        RECT 109.050 27.900 109.950 28.200 ;
        RECT 119.100 27.900 120.150 28.800 ;
        RECT 18.150 16.200 35.850 16.800 ;
        RECT 10.950 14.400 11.850 15.300 ;
        RECT 9.150 12.600 11.850 14.400 ;
        RECT 12.750 14.100 14.550 14.400 ;
        RECT 18.150 14.100 19.050 16.200 ;
        RECT 24.750 15.600 35.850 16.200 ;
        RECT 41.100 15.600 42.300 20.850 ;
        RECT 12.750 13.200 19.050 14.100 ;
        RECT 19.950 14.700 21.750 15.300 ;
        RECT 19.950 13.500 27.450 14.700 ;
        RECT 12.750 12.600 14.550 13.200 ;
        RECT 26.250 12.600 27.450 13.500 ;
        RECT 7.950 9.600 11.850 11.700 ;
        RECT 16.950 10.500 23.850 12.300 ;
        RECT 26.250 10.500 31.050 12.600 ;
        RECT 5.550 3.750 7.350 6.600 ;
        RECT 10.050 3.750 11.850 9.600 ;
        RECT 14.250 3.750 16.050 9.600 ;
        RECT 18.150 3.750 19.950 10.500 ;
        RECT 26.250 9.600 27.450 10.500 ;
        RECT 21.150 3.750 22.950 9.600 ;
        RECT 25.950 3.750 27.750 9.600 ;
        RECT 31.050 3.750 32.850 9.600 ;
        RECT 34.050 3.750 35.850 15.600 ;
        RECT 40.650 3.750 42.450 15.600 ;
        RECT 43.650 14.700 51.450 15.600 ;
        RECT 43.650 3.750 45.450 14.700 ;
        RECT 46.650 3.750 48.450 13.800 ;
        RECT 49.650 3.750 51.450 14.700 ;
        RECT 56.400 9.600 57.600 22.050 ;
        RECT 64.950 20.850 67.050 22.950 ;
        RECT 65.100 19.050 66.900 20.850 ;
        RECT 67.950 16.650 69.000 23.850 ;
        RECT 70.950 20.850 73.050 22.950 ;
        RECT 76.950 20.850 79.050 22.950 ;
        RECT 71.100 19.050 72.900 20.850 ;
        RECT 77.100 19.050 78.900 20.850 ;
        RECT 79.950 16.650 81.000 23.850 ;
        RECT 82.950 20.850 85.050 22.950 ;
        RECT 88.950 22.050 91.050 24.150 ;
        RECT 91.950 23.850 94.050 25.950 ;
        RECT 95.550 25.050 100.050 27.150 ;
        RECT 109.050 27.000 120.150 27.900 ;
        RECT 92.100 22.050 93.900 23.850 ;
        RECT 83.100 19.050 84.900 20.850 ;
        RECT 66.450 15.600 69.000 16.650 ;
        RECT 78.450 15.600 81.000 16.650 ;
        RECT 53.550 3.750 55.350 9.600 ;
        RECT 56.550 3.750 58.350 9.600 ;
        RECT 66.450 3.750 68.250 15.600 ;
        RECT 70.650 3.750 72.450 15.600 ;
        RECT 78.450 3.750 80.250 15.600 ;
        RECT 82.650 3.750 84.450 15.600 ;
        RECT 89.400 9.600 90.600 22.050 ;
        RECT 95.550 15.600 96.750 25.050 ;
        RECT 97.950 23.250 101.850 25.050 ;
        RECT 97.950 22.950 100.050 23.250 ;
        RECT 109.050 22.950 109.950 27.000 ;
        RECT 119.100 25.800 120.150 27.000 ;
        RECT 119.100 24.600 126.000 25.800 ;
        RECT 119.100 24.000 120.900 24.600 ;
        RECT 125.100 23.850 126.000 24.600 ;
        RECT 122.100 22.950 123.900 23.700 ;
        RECT 109.050 20.850 112.050 22.950 ;
        RECT 115.950 21.900 123.900 22.950 ;
        RECT 125.100 22.050 126.900 23.850 ;
        RECT 115.950 20.850 118.050 21.900 ;
        RECT 97.950 17.400 99.750 19.200 ;
        RECT 98.850 16.200 103.050 17.400 ;
        RECT 109.050 16.200 109.950 20.850 ;
        RECT 117.750 17.100 119.550 17.400 ;
        RECT 88.650 3.750 90.450 9.600 ;
        RECT 91.650 3.750 93.450 9.600 ;
        RECT 95.550 3.750 97.350 15.600 ;
        RECT 100.950 15.300 103.050 16.200 ;
        RECT 103.950 15.300 109.950 16.200 ;
        RECT 111.150 16.800 119.550 17.100 ;
        RECT 127.950 16.800 128.850 29.400 ;
        RECT 111.150 16.200 128.850 16.800 ;
        RECT 103.950 14.400 104.850 15.300 ;
        RECT 102.150 12.600 104.850 14.400 ;
        RECT 105.750 14.100 107.550 14.400 ;
        RECT 111.150 14.100 112.050 16.200 ;
        RECT 117.750 15.600 128.850 16.200 ;
        RECT 105.750 13.200 112.050 14.100 ;
        RECT 112.950 14.700 114.750 15.300 ;
        RECT 112.950 13.500 120.450 14.700 ;
        RECT 105.750 12.600 107.550 13.200 ;
        RECT 119.250 12.600 120.450 13.500 ;
        RECT 100.950 9.600 104.850 11.700 ;
        RECT 109.950 10.500 116.850 12.300 ;
        RECT 119.250 10.500 124.050 12.600 ;
        RECT 98.550 3.750 100.350 6.600 ;
        RECT 103.050 3.750 104.850 9.600 ;
        RECT 107.250 3.750 109.050 9.600 ;
        RECT 111.150 3.750 112.950 10.500 ;
        RECT 119.250 9.600 120.450 10.500 ;
        RECT 114.150 3.750 115.950 9.600 ;
        RECT 118.950 3.750 120.750 9.600 ;
        RECT 124.050 3.750 125.850 9.600 ;
        RECT 127.050 3.750 128.850 15.600 ;
      LAYER metal2 ;
        RECT 55.950 134.400 58.050 136.500 ;
        RECT 76.950 135.300 79.050 137.400 ;
        RECT 8.250 128.250 9.750 129.150 ;
        RECT 10.950 127.950 13.050 130.050 ;
        RECT 22.950 128.250 25.050 129.150 ;
        RECT 25.950 127.950 28.050 130.050 ;
        RECT 4.950 125.850 6.750 126.750 ;
        RECT 7.950 124.950 10.050 127.050 ;
        RECT 11.250 125.850 13.050 126.750 ;
        RECT 13.950 125.250 15.750 126.150 ;
        RECT 20.250 125.250 21.750 126.150 ;
        RECT 8.400 118.050 9.450 124.950 ;
        RECT 13.950 121.950 16.050 124.050 ;
        RECT 17.250 122.850 18.750 123.750 ;
        RECT 19.950 121.950 22.050 124.050 ;
        RECT 14.400 121.050 15.450 121.950 ;
        RECT 26.400 121.050 27.450 127.950 ;
        RECT 31.950 124.950 34.050 127.050 ;
        RECT 37.950 125.250 40.050 126.150 ;
        RECT 43.950 125.250 46.050 126.150 ;
        RECT 28.950 122.250 31.050 123.150 ;
        RECT 31.950 122.850 34.050 123.750 ;
        RECT 37.950 121.950 40.050 124.050 ;
        RECT 41.250 122.250 42.750 123.150 ;
        RECT 43.950 121.950 46.050 124.050 ;
        RECT 13.950 118.950 16.050 121.050 ;
        RECT 25.950 118.950 28.050 121.050 ;
        RECT 28.950 118.950 31.050 121.050 ;
        RECT 40.950 118.950 43.050 121.050 ;
        RECT 29.400 118.050 30.450 118.950 ;
        RECT 7.950 115.950 10.050 118.050 ;
        RECT 25.950 115.950 28.050 118.050 ;
        RECT 28.950 115.950 31.050 118.050 ;
        RECT 56.400 117.600 57.600 134.400 ;
        RECT 77.250 131.700 78.450 135.300 ;
        RECT 76.950 129.600 79.050 131.700 ;
        RECT 61.950 125.250 64.050 126.150 ;
        RECT 67.950 125.250 70.050 126.150 ;
        RECT 61.950 121.950 64.050 124.050 ;
        RECT 73.950 121.950 76.050 124.050 ;
        RECT 62.400 121.050 63.450 121.950 ;
        RECT 61.950 118.950 64.050 121.050 ;
        RECT 1.950 112.950 4.050 115.050 ;
        RECT 2.400 61.050 3.450 112.950 ;
        RECT 19.950 106.950 22.050 109.050 ;
        RECT 7.950 103.950 10.050 106.050 ;
        RECT 8.400 94.050 9.450 103.950 ;
        RECT 20.400 100.050 21.450 106.950 ;
        RECT 22.950 100.950 25.050 103.050 ;
        RECT 23.400 100.050 24.450 100.950 ;
        RECT 13.950 97.950 16.050 100.050 ;
        RECT 19.950 97.950 22.050 100.050 ;
        RECT 22.950 97.950 25.050 100.050 ;
        RECT 4.950 92.250 6.750 93.150 ;
        RECT 7.950 91.950 10.050 94.050 ;
        RECT 11.250 92.250 13.050 93.150 ;
        RECT 8.250 89.850 9.750 90.750 ;
        RECT 10.950 90.450 13.050 91.050 ;
        RECT 14.400 90.450 15.450 97.950 ;
        RECT 23.400 97.050 24.450 97.950 ;
        RECT 26.400 97.050 27.450 115.950 ;
        RECT 55.950 115.500 58.050 117.600 ;
        RECT 49.950 106.950 52.050 109.050 ;
        RECT 34.950 103.950 37.050 106.050 ;
        RECT 40.950 103.950 43.050 106.050 ;
        RECT 20.250 95.850 21.750 96.750 ;
        RECT 22.950 94.950 25.050 97.050 ;
        RECT 25.950 94.950 28.050 97.050 ;
        RECT 29.250 95.250 30.750 96.150 ;
        RECT 31.950 94.950 34.050 97.050 ;
        RECT 35.400 94.050 36.450 103.950 ;
        RECT 41.400 100.050 42.450 103.950 ;
        RECT 40.950 97.950 43.050 100.050 ;
        RECT 50.400 97.050 51.450 106.950 ;
        RECT 67.950 103.950 70.050 106.050 ;
        RECT 52.950 97.950 55.050 100.050 ;
        RECT 61.950 97.950 64.050 100.050 ;
        RECT 37.950 94.950 40.050 97.050 ;
        RECT 40.950 95.850 43.050 96.750 ;
        RECT 43.950 95.250 46.050 96.150 ;
        RECT 49.950 94.950 52.050 97.050 ;
        RECT 53.250 95.850 54.750 96.750 ;
        RECT 55.950 94.950 58.050 97.050 ;
        RECT 16.950 92.850 19.050 93.750 ;
        RECT 22.950 92.850 25.050 93.750 ;
        RECT 25.950 92.850 27.750 93.750 ;
        RECT 28.950 91.950 31.050 94.050 ;
        RECT 32.250 92.850 33.750 93.750 ;
        RECT 34.950 91.950 37.050 94.050 ;
        RECT 10.950 89.400 15.450 90.450 ;
        RECT 34.950 89.850 37.050 90.750 ;
        RECT 10.950 88.950 13.050 89.400 ;
        RECT 38.400 61.050 39.450 94.950 ;
        RECT 62.400 94.050 63.450 97.950 ;
        RECT 68.400 97.050 69.450 103.950 ;
        RECT 74.400 97.050 75.450 121.950 ;
        RECT 77.250 117.600 78.450 129.600 ;
        RECT 79.950 127.950 82.050 130.050 ;
        RECT 80.400 124.050 81.450 127.950 ;
        RECT 88.950 126.450 91.050 127.050 ;
        RECT 88.950 125.400 93.450 126.450 ;
        RECT 88.950 124.950 91.050 125.400 ;
        RECT 79.950 121.950 82.050 124.050 ;
        RECT 85.950 122.250 88.050 123.150 ;
        RECT 88.950 122.850 91.050 123.750 ;
        RECT 79.950 119.850 82.050 120.750 ;
        RECT 85.950 120.450 88.050 121.050 ;
        RECT 85.950 119.400 90.450 120.450 ;
        RECT 85.950 118.950 88.050 119.400 ;
        RECT 76.950 115.500 79.050 117.600 ;
        RECT 79.950 97.950 82.050 100.050 ;
        RECT 67.950 94.950 70.050 97.050 ;
        RECT 71.250 95.250 72.750 96.150 ;
        RECT 73.950 94.950 76.050 97.050 ;
        RECT 76.950 95.250 79.050 96.150 ;
        RECT 79.950 95.850 82.050 96.750 ;
        RECT 82.950 95.250 84.750 96.150 ;
        RECT 85.950 94.950 88.050 97.050 ;
        RECT 43.950 91.950 46.050 94.050 ;
        RECT 49.950 92.850 52.050 93.750 ;
        RECT 55.950 92.850 58.050 93.750 ;
        RECT 61.950 91.950 64.050 94.050 ;
        RECT 68.250 92.850 69.750 93.750 ;
        RECT 70.950 91.950 73.050 94.050 ;
        RECT 74.250 92.850 76.050 93.750 ;
        RECT 76.950 91.950 79.050 94.050 ;
        RECT 82.950 91.950 85.050 94.050 ;
        RECT 86.250 92.850 88.050 93.750 ;
        RECT 64.950 89.850 67.050 90.750 ;
        RECT 89.400 88.050 90.450 119.400 ;
        RECT 92.400 108.450 93.450 125.400 ;
        RECT 94.950 125.250 97.050 126.150 ;
        RECT 100.950 125.250 103.050 126.150 ;
        RECT 106.950 125.250 109.050 126.150 ;
        RECT 112.950 125.250 115.050 126.150 ;
        RECT 118.950 125.250 121.050 126.150 ;
        RECT 124.950 125.250 127.050 126.150 ;
        RECT 94.950 121.950 97.050 124.050 ;
        RECT 106.950 121.950 109.050 124.050 ;
        RECT 118.950 121.950 121.050 124.050 ;
        RECT 92.400 107.400 96.450 108.450 ;
        RECT 91.950 103.950 94.050 106.050 ;
        RECT 92.400 94.050 93.450 103.950 ;
        RECT 91.950 91.950 94.050 94.050 ;
        RECT 79.950 85.950 82.050 88.050 ;
        RECT 88.950 85.950 91.050 88.050 ;
        RECT 1.950 58.950 4.050 61.050 ;
        RECT 10.950 58.950 13.050 61.050 ;
        RECT 37.950 58.950 40.050 61.050 ;
        RECT 67.950 58.950 70.050 61.050 ;
        RECT 2.400 49.050 3.450 58.950 ;
        RECT 11.400 58.050 12.450 58.950 ;
        RECT 8.250 56.250 9.750 57.150 ;
        RECT 10.950 55.950 13.050 58.050 ;
        RECT 22.950 55.950 25.050 58.050 ;
        RECT 28.950 57.450 31.050 58.050 ;
        RECT 26.400 56.400 31.050 57.450 ;
        RECT 23.400 55.050 24.450 55.950 ;
        RECT 26.400 55.050 27.450 56.400 ;
        RECT 28.950 55.950 31.050 56.400 ;
        RECT 32.250 56.250 33.750 57.150 ;
        RECT 34.950 55.950 37.050 58.050 ;
        RECT 43.950 56.250 46.050 57.150 ;
        RECT 68.400 55.050 69.450 58.950 ;
        RECT 4.950 53.850 6.750 54.750 ;
        RECT 7.950 52.950 10.050 55.050 ;
        RECT 11.250 53.850 13.050 54.750 ;
        RECT 16.950 53.250 19.050 54.150 ;
        RECT 22.950 52.950 25.050 55.050 ;
        RECT 25.950 52.950 28.050 55.050 ;
        RECT 28.950 53.850 30.750 54.750 ;
        RECT 31.950 52.950 34.050 55.050 ;
        RECT 35.250 53.850 37.050 54.750 ;
        RECT 47.250 53.250 48.750 54.150 ;
        RECT 49.950 52.950 52.050 55.050 ;
        RECT 53.250 53.250 55.050 54.150 ;
        RECT 58.950 53.250 60.750 54.150 ;
        RECT 61.950 52.950 64.050 55.050 ;
        RECT 67.950 52.950 70.050 55.050 ;
        RECT 70.950 53.250 73.050 54.150 ;
        RECT 76.950 53.250 79.050 54.150 ;
        RECT 13.950 50.250 15.750 51.150 ;
        RECT 22.950 50.850 25.050 51.750 ;
        RECT 32.400 49.050 33.450 52.950 ;
        RECT 37.950 49.950 40.050 52.050 ;
        RECT 46.950 49.950 49.050 52.050 ;
        RECT 50.250 50.850 51.750 51.750 ;
        RECT 52.950 49.950 55.050 52.050 ;
        RECT 58.950 49.950 61.050 52.050 ;
        RECT 62.250 50.850 64.050 51.750 ;
        RECT 64.950 50.250 67.050 51.150 ;
        RECT 67.950 50.850 70.050 51.750 ;
        RECT 70.950 49.950 73.050 52.050 ;
        RECT 74.250 50.250 75.750 51.150 ;
        RECT 76.950 49.950 79.050 52.050 ;
        RECT 1.950 46.950 4.050 49.050 ;
        RECT 13.950 46.950 16.050 49.050 ;
        RECT 31.950 46.950 34.050 49.050 ;
        RECT 2.400 24.450 3.450 46.950 ;
        RECT 7.950 29.400 10.050 31.500 ;
        RECT 28.950 29.400 31.050 31.500 ;
        RECT 4.950 26.250 7.050 27.150 ;
        RECT 4.950 24.450 7.050 25.050 ;
        RECT 2.400 23.400 7.050 24.450 ;
        RECT 4.950 22.950 7.050 23.400 ;
        RECT 8.550 17.400 9.750 29.400 ;
        RECT 22.950 22.950 25.050 25.050 ;
        RECT 16.950 20.850 19.050 21.750 ;
        RECT 22.950 20.850 25.050 21.750 ;
        RECT 7.950 15.300 10.050 17.400 ;
        RECT 8.550 11.700 9.750 15.300 ;
        RECT 29.400 12.600 30.600 29.400 ;
        RECT 38.400 22.050 39.450 49.950 ;
        RECT 53.400 49.050 54.450 49.950 ;
        RECT 46.950 46.950 49.050 49.050 ;
        RECT 52.950 46.950 55.050 49.050 ;
        RECT 47.400 28.050 48.450 46.950 ;
        RECT 46.950 25.950 49.050 28.050 ;
        RECT 40.950 22.950 43.050 25.050 ;
        RECT 44.250 23.250 46.050 24.150 ;
        RECT 46.950 23.850 49.050 24.750 ;
        RECT 49.950 23.250 52.050 24.150 ;
        RECT 52.950 23.850 55.050 24.750 ;
        RECT 55.950 23.250 58.050 24.150 ;
        RECT 59.400 22.050 60.450 49.950 ;
        RECT 71.400 49.050 72.450 49.950 ;
        RECT 64.950 46.950 67.050 49.050 ;
        RECT 70.950 46.950 73.050 49.050 ;
        RECT 73.950 46.950 76.050 49.050 ;
        RECT 65.400 43.050 66.450 46.950 ;
        RECT 74.400 46.050 75.450 46.950 ;
        RECT 73.950 43.950 76.050 46.050 ;
        RECT 64.950 40.950 67.050 43.050 ;
        RECT 77.400 40.050 78.450 49.950 ;
        RECT 80.400 49.050 81.450 85.950 ;
        RECT 95.400 64.050 96.450 107.400 ;
        RECT 97.950 101.400 100.050 103.500 ;
        RECT 107.400 103.050 108.450 121.950 ;
        RECT 119.400 115.050 120.450 121.950 ;
        RECT 118.950 112.950 121.050 115.050 ;
        RECT 98.400 84.600 99.600 101.400 ;
        RECT 106.950 100.950 109.050 103.050 ;
        RECT 118.950 101.400 121.050 103.500 ;
        RECT 103.950 94.950 106.050 97.050 ;
        RECT 103.950 92.850 106.050 93.750 ;
        RECT 109.950 92.850 112.050 93.750 ;
        RECT 119.250 89.400 120.450 101.400 ;
        RECT 124.950 100.950 127.050 103.050 ;
        RECT 121.950 98.250 124.050 99.150 ;
        RECT 121.950 96.450 124.050 97.050 ;
        RECT 125.400 96.450 126.450 100.950 ;
        RECT 121.950 95.400 126.450 96.450 ;
        RECT 121.950 94.950 124.050 95.400 ;
        RECT 118.950 87.300 121.050 89.400 ;
        RECT 97.950 82.500 100.050 84.600 ;
        RECT 119.250 83.700 120.450 87.300 ;
        RECT 118.950 81.600 121.050 83.700 ;
        RECT 82.950 61.950 85.050 64.050 ;
        RECT 94.950 61.950 97.050 64.050 ;
        RECT 79.950 46.950 82.050 49.050 ;
        RECT 67.950 37.950 70.050 40.050 ;
        RECT 76.950 37.950 79.050 40.050 ;
        RECT 68.400 28.050 69.450 37.950 ;
        RECT 80.400 28.050 81.450 46.950 ;
        RECT 83.400 43.050 84.450 61.950 ;
        RECT 97.950 58.950 100.050 61.050 ;
        RECT 85.950 56.250 88.050 57.150 ;
        RECT 98.400 55.050 99.450 58.950 ;
        RECT 103.950 55.950 106.050 58.050 ;
        RECT 104.400 55.050 105.450 55.950 ;
        RECT 89.250 53.250 90.750 54.150 ;
        RECT 91.950 52.950 94.050 55.050 ;
        RECT 95.250 53.250 97.050 54.150 ;
        RECT 97.950 52.950 100.050 55.050 ;
        RECT 103.950 52.950 106.050 55.050 ;
        RECT 107.250 53.250 109.050 54.150 ;
        RECT 112.950 53.250 115.050 54.150 ;
        RECT 118.950 53.250 121.050 54.150 ;
        RECT 88.950 49.950 91.050 52.050 ;
        RECT 92.250 50.850 93.750 51.750 ;
        RECT 94.950 49.950 97.050 52.050 ;
        RECT 97.950 50.850 100.050 51.750 ;
        RECT 100.950 50.250 103.050 51.150 ;
        RECT 103.950 50.850 105.750 51.750 ;
        RECT 106.950 49.950 109.050 52.050 ;
        RECT 112.950 49.950 115.050 52.050 ;
        RECT 100.950 46.950 103.050 49.050 ;
        RECT 101.400 46.050 102.450 46.950 ;
        RECT 100.950 43.950 103.050 46.050 ;
        RECT 82.950 40.950 85.050 43.050 ;
        RECT 100.950 29.400 103.050 31.500 ;
        RECT 67.950 25.950 70.050 28.050 ;
        RECT 79.950 25.950 82.050 28.050 ;
        RECT 82.950 25.950 85.050 28.050 ;
        RECT 91.950 25.950 94.050 28.050 ;
        RECT 97.950 26.250 100.050 27.150 ;
        RECT 83.400 25.050 84.450 25.950 ;
        RECT 64.950 24.450 67.050 25.050 ;
        RECT 62.400 23.400 67.050 24.450 ;
        RECT 68.250 23.850 69.750 24.750 ;
        RECT 37.950 19.950 40.050 22.050 ;
        RECT 40.950 20.850 42.750 21.750 ;
        RECT 43.950 19.950 46.050 22.050 ;
        RECT 49.950 19.950 52.050 22.050 ;
        RECT 55.950 19.950 58.050 22.050 ;
        RECT 58.950 19.950 61.050 22.050 ;
        RECT 56.400 19.050 57.450 19.950 ;
        RECT 62.400 19.050 63.450 23.400 ;
        RECT 64.950 22.950 67.050 23.400 ;
        RECT 70.950 22.950 73.050 25.050 ;
        RECT 80.250 23.850 81.750 24.750 ;
        RECT 82.950 22.950 85.050 25.050 ;
        RECT 88.950 23.250 91.050 24.150 ;
        RECT 91.950 23.850 94.050 24.750 ;
        RECT 97.950 22.950 100.050 25.050 ;
        RECT 64.950 20.850 67.050 21.750 ;
        RECT 70.950 20.850 73.050 21.750 ;
        RECT 76.950 20.850 79.050 21.750 ;
        RECT 82.950 20.850 85.050 21.750 ;
        RECT 88.950 19.950 91.050 22.050 ;
        RECT 55.950 16.950 58.050 19.050 ;
        RECT 61.950 16.950 64.050 19.050 ;
        RECT 101.550 17.400 102.750 29.400 ;
        RECT 107.400 25.050 108.450 49.950 ;
        RECT 113.400 28.050 114.450 49.950 ;
        RECT 121.950 29.400 124.050 31.500 ;
        RECT 112.950 25.950 115.050 28.050 ;
        RECT 106.950 22.950 109.050 25.050 ;
        RECT 115.950 22.950 118.050 25.050 ;
        RECT 109.950 20.850 112.050 21.750 ;
        RECT 115.950 20.850 118.050 21.750 ;
        RECT 100.950 15.300 103.050 17.400 ;
        RECT 7.950 9.600 10.050 11.700 ;
        RECT 28.950 10.500 31.050 12.600 ;
        RECT 101.550 11.700 102.750 15.300 ;
        RECT 122.400 12.600 123.600 29.400 ;
        RECT 100.950 9.600 103.050 11.700 ;
        RECT 121.950 10.500 124.050 12.600 ;
      LAYER metal3 ;
        RECT 10.950 129.600 13.050 130.050 ;
        RECT 25.950 129.600 28.050 130.050 ;
        RECT 79.950 129.600 82.050 130.050 ;
        RECT 10.950 128.400 82.050 129.600 ;
        RECT 10.950 127.950 13.050 128.400 ;
        RECT 25.950 127.950 28.050 128.400 ;
        RECT 79.950 127.950 82.050 128.400 ;
        RECT 31.950 126.600 34.050 127.050 ;
        RECT 31.950 125.400 45.600 126.600 ;
        RECT 31.950 124.950 34.050 125.400 ;
        RECT 44.400 124.050 45.600 125.400 ;
        RECT 19.950 123.600 22.050 124.050 ;
        RECT 37.950 123.600 40.050 124.050 ;
        RECT 19.950 122.400 40.050 123.600 ;
        RECT 19.950 121.950 22.050 122.400 ;
        RECT 37.950 121.950 40.050 122.400 ;
        RECT 43.950 123.600 46.050 124.050 ;
        RECT 73.950 123.600 76.050 124.050 ;
        RECT 43.950 122.400 76.050 123.600 ;
        RECT 43.950 121.950 46.050 122.400 ;
        RECT 73.950 121.950 76.050 122.400 ;
        RECT 79.950 123.600 82.050 124.050 ;
        RECT 94.950 123.600 97.050 124.050 ;
        RECT 79.950 122.400 97.050 123.600 ;
        RECT 79.950 121.950 82.050 122.400 ;
        RECT 94.950 121.950 97.050 122.400 ;
        RECT 13.950 120.600 16.050 121.050 ;
        RECT 25.950 120.600 28.050 121.050 ;
        RECT 13.950 119.400 28.050 120.600 ;
        RECT 13.950 118.950 16.050 119.400 ;
        RECT 25.950 118.950 28.050 119.400 ;
        RECT 40.950 120.600 43.050 121.050 ;
        RECT 61.950 120.600 64.050 121.050 ;
        RECT 40.950 119.400 64.050 120.600 ;
        RECT 40.950 118.950 43.050 119.400 ;
        RECT 61.950 118.950 64.050 119.400 ;
        RECT 7.950 117.600 10.050 118.050 ;
        RECT 25.950 117.600 28.050 118.050 ;
        RECT 28.950 117.600 31.050 118.050 ;
        RECT 7.950 116.400 31.050 117.600 ;
        RECT 7.950 115.950 10.050 116.400 ;
        RECT 25.950 115.950 28.050 116.400 ;
        RECT 28.950 115.950 31.050 116.400 ;
        RECT 1.950 114.600 4.050 115.050 ;
        RECT 118.950 114.600 121.050 115.050 ;
        RECT 1.950 113.400 121.050 114.600 ;
        RECT 1.950 112.950 4.050 113.400 ;
        RECT 118.950 112.950 121.050 113.400 ;
        RECT 19.950 108.600 22.050 109.050 ;
        RECT 49.950 108.600 52.050 109.050 ;
        RECT 19.950 107.400 52.050 108.600 ;
        RECT 19.950 106.950 22.050 107.400 ;
        RECT 49.950 106.950 52.050 107.400 ;
        RECT 7.950 105.600 10.050 106.050 ;
        RECT 34.950 105.600 37.050 106.050 ;
        RECT 40.950 105.600 43.050 106.050 ;
        RECT 7.950 104.400 43.050 105.600 ;
        RECT 7.950 103.950 10.050 104.400 ;
        RECT 34.950 103.950 37.050 104.400 ;
        RECT 40.950 103.950 43.050 104.400 ;
        RECT 67.950 105.600 70.050 106.050 ;
        RECT 91.950 105.600 94.050 106.050 ;
        RECT 67.950 104.400 94.050 105.600 ;
        RECT 67.950 103.950 70.050 104.400 ;
        RECT 91.950 103.950 94.050 104.400 ;
        RECT 22.950 102.600 25.050 103.050 ;
        RECT 106.950 102.600 109.050 103.050 ;
        RECT 124.950 102.600 127.050 103.050 ;
        RECT 22.950 101.400 127.050 102.600 ;
        RECT 22.950 100.950 25.050 101.400 ;
        RECT 106.950 100.950 109.050 101.400 ;
        RECT 124.950 100.950 127.050 101.400 ;
        RECT 13.950 99.600 16.050 100.050 ;
        RECT 22.950 99.600 25.050 100.050 ;
        RECT 13.950 98.400 25.050 99.600 ;
        RECT 13.950 97.950 16.050 98.400 ;
        RECT 22.950 97.950 25.050 98.400 ;
        RECT 52.950 99.600 55.050 100.050 ;
        RECT 61.950 99.600 64.050 100.050 ;
        RECT 79.950 99.600 82.050 100.050 ;
        RECT 52.950 98.400 82.050 99.600 ;
        RECT 52.950 97.950 55.050 98.400 ;
        RECT 61.950 97.950 64.050 98.400 ;
        RECT 79.950 97.950 82.050 98.400 ;
        RECT 31.950 96.600 34.050 97.050 ;
        RECT 37.950 96.600 40.050 97.050 ;
        RECT 49.950 96.600 52.050 97.050 ;
        RECT 31.950 95.400 40.050 96.600 ;
        RECT 31.950 94.950 34.050 95.400 ;
        RECT 37.950 94.950 40.050 95.400 ;
        RECT 41.400 95.400 52.050 96.600 ;
        RECT 28.950 93.600 31.050 94.050 ;
        RECT 41.400 93.600 42.600 95.400 ;
        RECT 49.950 94.950 52.050 95.400 ;
        RECT 55.950 94.950 58.050 97.050 ;
        RECT 73.950 96.600 76.050 97.050 ;
        RECT 85.950 96.600 88.050 97.050 ;
        RECT 103.950 96.600 106.050 97.050 ;
        RECT 73.950 95.400 78.600 96.600 ;
        RECT 73.950 94.950 76.050 95.400 ;
        RECT 28.950 92.400 42.600 93.600 ;
        RECT 43.950 93.600 46.050 94.050 ;
        RECT 56.400 93.600 57.600 94.950 ;
        RECT 77.400 94.050 78.600 95.400 ;
        RECT 85.950 95.400 106.050 96.600 ;
        RECT 85.950 94.950 88.050 95.400 ;
        RECT 103.950 94.950 106.050 95.400 ;
        RECT 43.950 92.400 57.600 93.600 ;
        RECT 61.950 93.600 64.050 94.050 ;
        RECT 70.950 93.600 73.050 94.050 ;
        RECT 61.950 92.400 73.050 93.600 ;
        RECT 28.950 91.950 31.050 92.400 ;
        RECT 43.950 91.950 46.050 92.400 ;
        RECT 61.950 91.950 64.050 92.400 ;
        RECT 70.950 91.950 73.050 92.400 ;
        RECT 76.950 91.950 79.050 94.050 ;
        RECT 82.950 93.600 85.050 94.050 ;
        RECT 91.950 93.600 94.050 94.050 ;
        RECT 82.950 92.400 94.050 93.600 ;
        RECT 82.950 91.950 85.050 92.400 ;
        RECT 91.950 91.950 94.050 92.400 ;
        RECT 79.950 87.600 82.050 88.050 ;
        RECT 88.950 87.600 91.050 88.050 ;
        RECT 79.950 86.400 91.050 87.600 ;
        RECT 79.950 85.950 82.050 86.400 ;
        RECT 88.950 85.950 91.050 86.400 ;
        RECT 82.950 63.600 85.050 64.050 ;
        RECT 94.950 63.600 97.050 64.050 ;
        RECT 82.950 62.400 97.050 63.600 ;
        RECT 82.950 61.950 85.050 62.400 ;
        RECT 94.950 61.950 97.050 62.400 ;
        RECT 1.950 60.600 4.050 61.050 ;
        RECT 10.950 60.600 13.050 61.050 ;
        RECT 1.950 59.400 13.050 60.600 ;
        RECT 1.950 58.950 4.050 59.400 ;
        RECT 10.950 58.950 13.050 59.400 ;
        RECT 37.950 60.600 40.050 61.050 ;
        RECT 67.950 60.600 70.050 61.050 ;
        RECT 97.950 60.600 100.050 61.050 ;
        RECT 37.950 59.400 100.050 60.600 ;
        RECT 37.950 58.950 40.050 59.400 ;
        RECT 67.950 58.950 70.050 59.400 ;
        RECT 97.950 58.950 100.050 59.400 ;
        RECT 22.950 57.600 25.050 58.050 ;
        RECT 34.950 57.600 37.050 58.050 ;
        RECT 103.950 57.600 106.050 58.050 ;
        RECT 22.950 56.400 37.050 57.600 ;
        RECT 22.950 55.950 25.050 56.400 ;
        RECT 34.950 55.950 37.050 56.400 ;
        RECT 89.400 56.400 106.050 57.600 ;
        RECT 7.950 54.600 10.050 55.050 ;
        RECT 25.950 54.600 28.050 55.050 ;
        RECT 7.950 53.400 28.050 54.600 ;
        RECT 7.950 52.950 10.050 53.400 ;
        RECT 25.950 52.950 28.050 53.400 ;
        RECT 49.950 52.950 52.050 55.050 ;
        RECT 61.950 52.950 64.050 55.050 ;
        RECT 37.950 51.600 40.050 52.050 ;
        RECT 46.950 51.600 49.050 52.050 ;
        RECT 37.950 50.400 49.050 51.600 ;
        RECT 50.400 51.600 51.600 52.950 ;
        RECT 58.950 51.600 61.050 52.050 ;
        RECT 50.400 50.400 61.050 51.600 ;
        RECT 62.400 51.600 63.600 52.950 ;
        RECT 89.400 52.050 90.600 56.400 ;
        RECT 103.950 55.950 106.050 56.400 ;
        RECT 91.950 52.950 94.050 55.050 ;
        RECT 97.950 54.600 100.050 55.050 ;
        RECT 95.400 53.400 100.050 54.600 ;
        RECT 76.950 51.600 79.050 52.050 ;
        RECT 62.400 50.400 79.050 51.600 ;
        RECT 37.950 49.950 40.050 50.400 ;
        RECT 46.950 49.950 49.050 50.400 ;
        RECT 58.950 49.950 61.050 50.400 ;
        RECT 76.950 49.950 79.050 50.400 ;
        RECT 88.950 49.950 91.050 52.050 ;
        RECT 1.950 48.600 4.050 49.050 ;
        RECT 13.950 48.600 16.050 49.050 ;
        RECT 1.950 47.400 16.050 48.600 ;
        RECT 1.950 46.950 4.050 47.400 ;
        RECT 13.950 46.950 16.050 47.400 ;
        RECT 31.950 48.600 34.050 49.050 ;
        RECT 46.950 48.600 49.050 49.050 ;
        RECT 52.950 48.600 55.050 49.050 ;
        RECT 31.950 47.400 55.050 48.600 ;
        RECT 31.950 46.950 34.050 47.400 ;
        RECT 46.950 46.950 49.050 47.400 ;
        RECT 52.950 46.950 55.050 47.400 ;
        RECT 70.950 48.600 73.050 49.050 ;
        RECT 79.950 48.600 82.050 49.050 ;
        RECT 70.950 47.400 82.050 48.600 ;
        RECT 92.400 48.600 93.600 52.950 ;
        RECT 95.400 52.050 96.600 53.400 ;
        RECT 97.950 52.950 100.050 53.400 ;
        RECT 94.950 49.950 97.050 52.050 ;
        RECT 100.950 48.600 103.050 49.050 ;
        RECT 92.400 47.400 103.050 48.600 ;
        RECT 70.950 46.950 73.050 47.400 ;
        RECT 79.950 46.950 82.050 47.400 ;
        RECT 100.950 46.950 103.050 47.400 ;
        RECT 73.950 45.600 76.050 46.050 ;
        RECT 100.950 45.600 103.050 46.050 ;
        RECT 73.950 44.400 103.050 45.600 ;
        RECT 73.950 43.950 76.050 44.400 ;
        RECT 100.950 43.950 103.050 44.400 ;
        RECT 64.950 42.600 67.050 43.050 ;
        RECT 82.950 42.600 85.050 43.050 ;
        RECT 64.950 41.400 85.050 42.600 ;
        RECT 64.950 40.950 67.050 41.400 ;
        RECT 82.950 40.950 85.050 41.400 ;
        RECT 67.950 39.600 70.050 40.050 ;
        RECT 76.950 39.600 79.050 40.050 ;
        RECT 67.950 38.400 79.050 39.600 ;
        RECT 67.950 37.950 70.050 38.400 ;
        RECT 76.950 37.950 79.050 38.400 ;
        RECT 82.950 27.600 85.050 28.050 ;
        RECT 91.950 27.600 94.050 28.050 ;
        RECT 112.950 27.600 115.050 28.050 ;
        RECT 82.950 26.400 115.050 27.600 ;
        RECT 82.950 25.950 85.050 26.400 ;
        RECT 91.950 25.950 94.050 26.400 ;
        RECT 112.950 25.950 115.050 26.400 ;
        RECT 22.950 24.600 25.050 25.050 ;
        RECT 40.950 24.600 43.050 25.050 ;
        RECT 22.950 23.400 43.050 24.600 ;
        RECT 22.950 22.950 25.050 23.400 ;
        RECT 40.950 22.950 43.050 23.400 ;
        RECT 70.950 22.950 73.050 25.050 ;
        RECT 82.950 24.600 85.050 25.050 ;
        RECT 97.950 24.600 100.050 25.050 ;
        RECT 82.950 23.400 100.050 24.600 ;
        RECT 82.950 22.950 85.050 23.400 ;
        RECT 97.950 22.950 100.050 23.400 ;
        RECT 106.950 24.600 109.050 25.050 ;
        RECT 115.950 24.600 118.050 25.050 ;
        RECT 106.950 23.400 118.050 24.600 ;
        RECT 106.950 22.950 109.050 23.400 ;
        RECT 115.950 22.950 118.050 23.400 ;
        RECT 37.950 21.600 40.050 22.050 ;
        RECT 43.950 21.600 46.050 22.050 ;
        RECT 37.950 20.400 46.050 21.600 ;
        RECT 37.950 19.950 40.050 20.400 ;
        RECT 43.950 19.950 46.050 20.400 ;
        RECT 49.950 21.600 52.050 22.050 ;
        RECT 58.950 21.600 61.050 22.050 ;
        RECT 49.950 20.400 61.050 21.600 ;
        RECT 71.400 21.600 72.600 22.950 ;
        RECT 88.950 21.600 91.050 22.050 ;
        RECT 71.400 20.400 91.050 21.600 ;
        RECT 49.950 19.950 52.050 20.400 ;
        RECT 58.950 19.950 61.050 20.400 ;
        RECT 88.950 19.950 91.050 20.400 ;
        RECT 55.950 18.600 58.050 19.050 ;
        RECT 61.950 18.600 64.050 19.050 ;
        RECT 55.950 17.400 64.050 18.600 ;
        RECT 55.950 16.950 58.050 17.400 ;
        RECT 61.950 16.950 64.050 17.400 ;
  END
END accumulator_4bit
END LIBRARY

